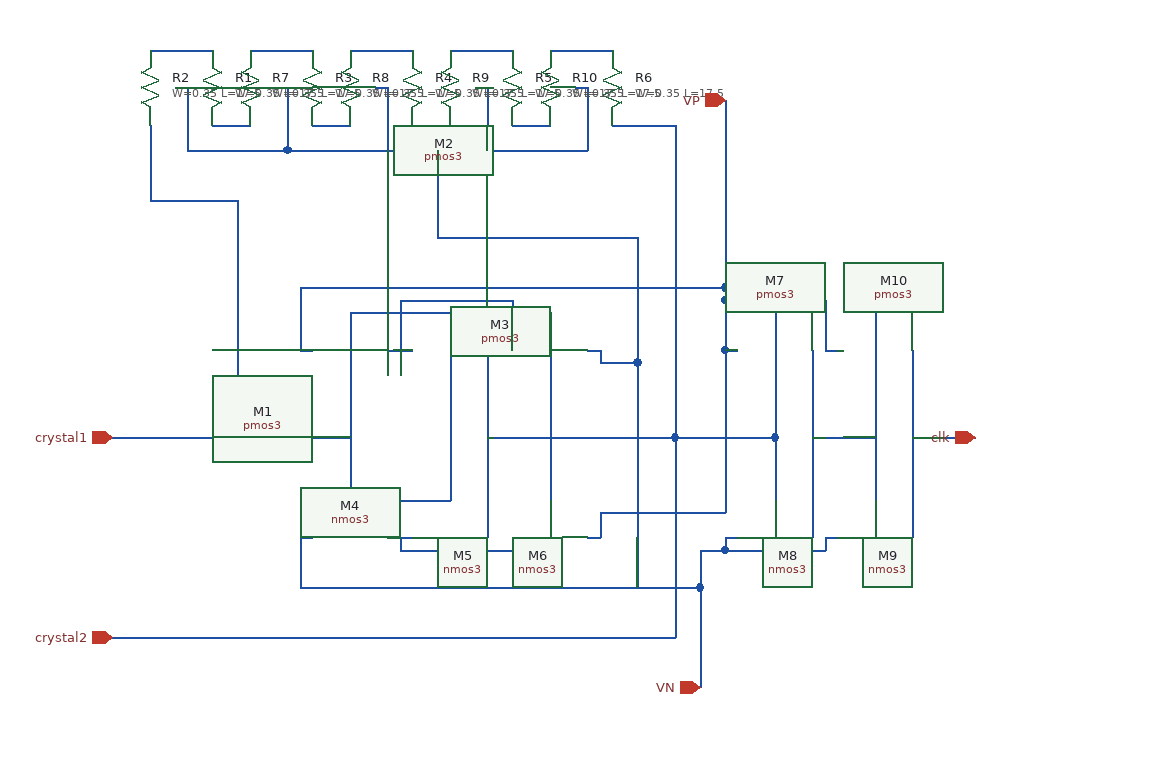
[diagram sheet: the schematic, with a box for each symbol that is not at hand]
v {xschem version=2.9.9 file_version=1.2 }
G {}
K {}
V {}
S {}
E {}
N 790 -830 810 -830 { lab=#net1}
N 920 -860 920 -710 { lab=crystal2}
N 840 -860 840 -710 { lab=crystal1}
N 760 -860 760 -710 { lab=crystal1}
N 870 -830 870 -680 { lab=crystal2}
N 790 -680 810 -680 { lab=#net2}
N 720 -680 730 -680 { lab=VN}
N 720 -680 720 -670 { lab=VN}
N 720 -830 730 -830 { lab=clk}
N 720 -840 720 -830 { lab=clk}
N 760 -710 840 -710 { lab=crystal1}
N 760 -860 840 -860 { lab=crystal1}
N 870 -760 920 -760 { lab=crystal2}
N 890 -870 890 -830 { lab=#net1}
N 800 -870 890 -870 { lab=#net1}
N 800 -870 800 -830 { lab=#net1}
N 890 -680 890 -670 { lab=#net2}
N 800 -670 890 -670 { lab=#net2}
N 800 -680 800 -670 { lab=#net2}
N 950 -830 960 -830 { lab=VN}
N 960 -830 960 -820 { lab=VN}
N 950 -680 960 -680 { lab=clk}
N 960 -690 960 -680 { lab=clk}
N 920 -760 1020 -760 { lab=crystal2}
N 670 -760 760 -760 { lab=crystal1}
N 670 -950 670 -760 { lab=crystal1}
N 1020 -950 1020 -760 { lab=crystal2}
N 1020 -760 1020 -600 { lab=crystal2}
N 670 -600 1020 -600 { lab=crystal2}
N 830 -930 830 -920 { lab=VN}
N 630 -760 670 -760 { lab=crystal1}
N 630 -600 670 -600 { lab=crystal2}
N 570 -760 630 -760 { lab=crystal1}
N 570 -600 630 -600 { lab=crystal2}
N 1020 -760 1070 -760 { lab=crystal2}
N 1070 -760 1100 -760 { lab=crystal2}
N 1100 -760 1100 -710 { lab=crystal2}
N 1100 -860 1100 -760 { lab=crystal2}
N 1130 -830 1130 -680 { lab=#net3}
N 1060 -680 1070 -680 { lab=VN}
N 1060 -680 1060 -670 { lab=VN}
N 1060 -830 1070 -830 { lab=clk}
N 1060 -840 1060 -830 { lab=clk}
N 1180 -860 1180 -710 { lab=#net3}
N 1130 -760 1180 -760 { lab=#net3}
N 1210 -830 1210 -680 { lab=clk}
N 1140 -830 1150 -830 { lab=clk}
N 1140 -840 1140 -830 { lab=clk}
N 1140 -680 1150 -680 { lab=VN}
N 1140 -680 1140 -670 { lab=VN}
N 1210 -760 1260 -760 { lab=clk}
N 1060 -870 1060 -840 { lab=clk}
N 1060 -870 1140 -870 { lab=clk}
N 1140 -870 1140 -840 { lab=clk}
N 1060 -670 1140 -670 { lab=VN}
N 720 -670 720 -640 { lab=VN}
N 720 -640 1040 -640 { lab=VN}
N 1040 -670 1040 -640 { lab=VN}
N 1040 -670 1060 -670 { lab=VN}
N 960 -820 990 -820 { lab=VN}
N 990 -820 990 -640 { lab=VN}
N 960 -700 1060 -700 { lab=clk}
N 1060 -830 1060 -700 { lab=clk}
N 960 -700 960 -690 { lab=clk}
N 720 -880 720 -840 { lab=clk}
N 720 -880 1040 -880 { lab=clk}
N 1060 -880 1060 -870 { lab=clk}
N 1040 -880 1060 -880 { lab=clk}
N 1060 -1030 1060 -880 { lab=clk}
N 1040 -640 1040 -560 { lab=VN}
N 830 -920 990 -920 { lab=VN}
N 990 -920 990 -820 { lab=VN}
N 600 -950 670 -950 { lab=crystal1}
N 600 -1010 600 -950 { lab=crystal1}
N 600 -1070 650 -1070 { lab=#net4}
N 650 -1010 680 -1010 { lab=#net5}
N 680 -1070 730 -1070 { lab=#net6}
N 730 -1010 760 -1010 { lab=#net7}
N 760 -1070 810 -1070 { lab=#net8}
N 810 -1010 840 -1010 { lab=#net9}
N 840 -1070 890 -1070 { lab=#net10}
N 890 -1010 920 -1010 { lab=#net11}
N 920 -1070 970 -1070 { lab=#net12}
N 970 -1010 1020 -1010 { lab=crystal2}
N 1020 -1010 1020 -950 { lab=crystal2}
N 940 -1040 950 -1040 { lab=VN}
N 860 -1040 870 -1040 { lab=VN}
N 780 -1040 790 -1040 { lab=VN}
N 700 -1040 710 -1040 { lab=VN}
N 620 -1040 630 -1040 { lab=VN}
N 630 -1040 630 -990 { lab=VN}
N 630 -990 710 -990 { lab=VN}
N 710 -1040 710 -990 { lab=VN}
N 790 -1040 790 -990 { lab=VN}
N 870 -1040 870 -990 { lab=VN}
N 950 -1040 950 -990 { lab=VN}
N 710 -990 950 -990 { lab=VN}
N 830 -990 830 -930 { lab=VN}
C {madvlsi/pmos3.sym} 760 -830 1 0 {name=M1
L=0.15
W=1
body=VDD
nf=1
mult=1
ad="'int((nf+1)/2) * W/nf * 0.29'" 
pd="'2*int((nf+1)/2) * (W/nf + 0.29)'"
as="'int((nf+2)/2) * W/nf * 0.29'" 
ps="'2*int((nf+2)/2) * (W/nf + 0.29)'"
nrd="'0.29 / W'" nrs="'0.29 / W'"
sa=0 sb=0 sd=0
model=pfet_01v8
spiceprefix=X
}
C {madvlsi/pmos3.sym} 840 -830 1 0 {name=M2
L=0.15
W=1
body=VDD
nf=1
mult=1
ad="'int((nf+1)/2) * W/nf * 0.29'" 
pd="'2*int((nf+1)/2) * (W/nf + 0.29)'"
as="'int((nf+2)/2) * W/nf * 0.29'" 
ps="'2*int((nf+2)/2) * (W/nf + 0.29)'"
nrd="'0.29 / W'" nrs="'0.29 / W'"
sa=0 sb=0 sd=0
model=pfet_01v8
spiceprefix=X
}
C {madvlsi/pmos3.sym} 920 -830 1 0 {name=M3
L=0.15
W=1
body=VDD
nf=1
mult=1
ad="'int((nf+1)/2) * W/nf * 0.29'" 
pd="'2*int((nf+1)/2) * (W/nf + 0.29)'"
as="'int((nf+2)/2) * W/nf * 0.29'" 
ps="'2*int((nf+2)/2) * (W/nf + 0.29)'"
nrd="'0.29 / W'" nrs="'0.29 / W'"
sa=0 sb=0 sd=0
model=pfet_01v8
spiceprefix=X
}
C {madvlsi/nmos3.sym} 760 -680 1 0 {name=M4
L=0.15
W=1
body=GND
nf=1
mult=1
ad="'int((nf+1)/2) * W/nf * 0.29'" 
pd="'2*int((nf+1)/2) * (W/nf + 0.29)'"
as="'int((nf+2)/2) * W/nf * 0.29'" 
ps="'2*int((nf+2)/2) * (W/nf + 0.29)'"
nrd="'0.29 / W'" nrs="'0.29 / W'"
sa=0 sb=0 sd=0
model=nfet_01v8
spiceprefix=X
}
C {madvlsi/nmos3.sym} 840 -680 1 0 {name=M5
L=0.15
W=1
body=GND
nf=1
mult=1
ad="'int((nf+1)/2) * W/nf * 0.29'" 
pd="'2*int((nf+1)/2) * (W/nf + 0.29)'"
as="'int((nf+2)/2) * W/nf * 0.29'" 
ps="'2*int((nf+2)/2) * (W/nf + 0.29)'"
nrd="'0.29 / W'" nrs="'0.29 / W'"
sa=0 sb=0 sd=0
model=nfet_01v8
spiceprefix=X
}
C {madvlsi/nmos3.sym} 920 -680 1 0 {name=M6
L=0.15
W=1
body=GND
nf=1
mult=1
ad="'int((nf+1)/2) * W/nf * 0.29'" 
pd="'2*int((nf+1)/2) * (W/nf + 0.29)'"
as="'int((nf+2)/2) * W/nf * 0.29'" 
ps="'2*int((nf+2)/2) * (W/nf + 0.29)'"
nrd="'0.29 / W'" nrs="'0.29 / W'"
sa=0 sb=0 sd=0
model=nfet_01v8
spiceprefix=X
}
C {sky130_fd_pr/res_xhigh_po.sym} 600 -1040 2 0 {name=R2
W=0.35
L=17.5
model=res_xhigh_po
spiceprefix=X
mult=1}
C {devices/iopin.sym} 570 -760 2 0 {name=p1 lab=crystal1}
C {devices/iopin.sym} 570 -600 2 0 {name=p2 lab=crystal2}
C {madvlsi/pmos3.sym} 1100 -830 1 0 {name=M7
L=0.15
W=1
body=VDD
nf=1
mult=1
ad="'int((nf+1)/2) * W/nf * 0.29'" 
pd="'2*int((nf+1)/2) * (W/nf + 0.29)'"
as="'int((nf+2)/2) * W/nf * 0.29'" 
ps="'2*int((nf+2)/2) * (W/nf + 0.29)'"
nrd="'0.29 / W'" nrs="'0.29 / W'"
sa=0 sb=0 sd=0
model=pfet_01v8
spiceprefix=X
}
C {madvlsi/nmos3.sym} 1100 -680 1 0 {name=M8
L=0.15
W=1
body=GND
nf=1
mult=1
ad="'int((nf+1)/2) * W/nf * 0.29'" 
pd="'2*int((nf+1)/2) * (W/nf + 0.29)'"
as="'int((nf+2)/2) * W/nf * 0.29'" 
ps="'2*int((nf+2)/2) * (W/nf + 0.29)'"
nrd="'0.29 / W'" nrs="'0.29 / W'"
sa=0 sb=0 sd=0
model=nfet_01v8
spiceprefix=X
}
C {madvlsi/nmos3.sym} 1180 -680 1 0 {name=M9
L=0.5
W=5
body=GND
nf=1
mult=1
ad="'int((nf+1)/2) * W/nf * 0.29'" 
pd="'2*int((nf+1)/2) * (W/nf + 0.29)'"
as="'int((nf+2)/2) * W/nf * 0.29'" 
ps="'2*int((nf+2)/2) * (W/nf + 0.29)'"
nrd="'0.29 / W'" nrs="'0.29 / W'"
sa=0 sb=0 sd=0
model=nfet_01v8
spiceprefix=X
}
C {madvlsi/pmos3.sym} 1180 -830 1 0 {name=M10
L=0.5
W=5
body=VDD
nf=1
mult=1
ad="'int((nf+1)/2) * W/nf * 0.29'" 
pd="'2*int((nf+1)/2) * (W/nf + 0.29)'"
as="'int((nf+2)/2) * W/nf * 0.29'" 
ps="'2*int((nf+2)/2) * (W/nf + 0.29)'"
nrd="'0.29 / W'" nrs="'0.29 / W'"
sa=0 sb=0 sd=0
model=pfet_01v8
spiceprefix=X
}
C {devices/iopin.sym} 1260 -760 0 0 {name=p3 lab=clk}
C {sky130_fd_pr/res_xhigh_po.sym} 650 -1040 0 0 {name=R1
W=0.35
L=17.5
model=res_xhigh_po
spiceprefix=X
mult=1}
C {sky130_fd_pr/res_xhigh_po.sym} 730 -1040 0 0 {name=R3
W=0.35
L=17.5
model=res_xhigh_po
spiceprefix=X
mult=1}
C {sky130_fd_pr/res_xhigh_po.sym} 810 -1040 0 0 {name=R4
W=0.35
L=17.5
model=res_xhigh_po
spiceprefix=X
mult=1}
C {sky130_fd_pr/res_xhigh_po.sym} 890 -1040 0 0 {name=R5
W=0.35
L=17.5
model=res_xhigh_po
spiceprefix=X
mult=1}
C {sky130_fd_pr/res_xhigh_po.sym} 970 -1040 0 0 {name=R6
W=0.35
L=17.5
model=res_xhigh_po
spiceprefix=X
mult=1}
C {sky130_fd_pr/res_xhigh_po.sym} 680 -1040 2 0 {name=R7
W=0.35
L=17.5
model=res_xhigh_po
spiceprefix=X
mult=1}
C {sky130_fd_pr/res_xhigh_po.sym} 760 -1040 2 0 {name=R8
W=0.35
L=17.5
model=res_xhigh_po
spiceprefix=X
mult=1}
C {sky130_fd_pr/res_xhigh_po.sym} 840 -1040 2 0 {name=R9
W=0.35
L=17.5
model=res_xhigh_po
spiceprefix=X
mult=1}
C {sky130_fd_pr/res_xhigh_po.sym} 920 -1040 2 0 {name=R10
W=0.35
L=17.5
model=res_xhigh_po
spiceprefix=X
mult=1}
C {devices/iopin.sym} 1040 -560 1 0 {name=p4 lab=VN}
C {devices/iopin.sym} 1060 -1030 3 0 {name=p5 lab=VP}
